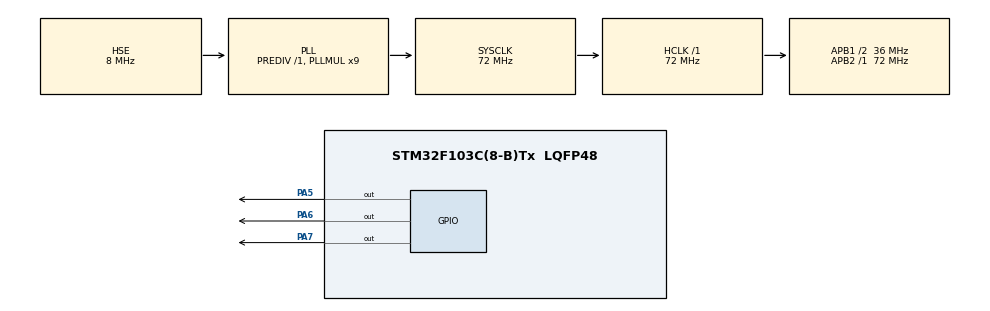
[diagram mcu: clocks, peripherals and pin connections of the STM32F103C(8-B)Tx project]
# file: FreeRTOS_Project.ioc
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Mcu.Family=STM32F1
Mcu.Name=STM32F103C(8-B)Tx
Mcu.Package=LQFP48
NVIC.PriorityGroup=NVIC_PRIORITYGROUP_4
NVIC.TIM2_IRQn=true\:15\:0\:false\:false\:true\:false\:true\:true
NVIC.TimeBase=TIM2_IRQn
NVIC.TimeBaseIP=TIM2
PA2.Signal=USART2_TX
PA3.Signal=USART2_RX
PA5.GPIO_PuPd=GPIO_PULLDOWN
PA5.Signal=GPIO_Output
PA6.GPIO_PuPd=GPIO_PULLDOWN
PA6.Signal=GPIO_Output
PA7.GPIO_PuPd=GPIO_PULLDOWN
PA7.Signal=GPIO_Output
PD0-OSC_IN.Mode=HSE-External-Oscillator
PD0-OSC_IN.Signal=RCC_OSC_IN
PD1-OSC_OUT.Mode=HSE-External-Oscillator
PD1-OSC_OUT.Signal=RCC_OSC_OUT
ProjectManager.HeapSize=0x200
ProjectManager.StackSize=0x400
ProjectManager.TargetToolchain=STM32CubeIDE
RCC.AHBFreq_Value=72000000
RCC.APB1CLKDivider=RCC_HCLK_DIV2
RCC.APB1Freq_Value=36000000
RCC.APB1TimFreq_Value=72000000
RCC.APB2Freq_Value=72000000
RCC.APB2TimFreq_Value=72000000
RCC.HCLKFreq_Value=72000000
RCC.PLLMUL=RCC_PLL_MUL9
RCC.PLLSourceVirtual=RCC_PLLSOURCE_HSE
RCC.SYSCLKFreq_VALUE=72000000
RCC.SYSCLKSource=RCC_SYSCLKSOURCE_PLLCLK
RCC.USBFreq_Value=72000000
VP_SYS_VS_ND.Mode=No_Debug
VP_SYS_VS_tim2.Mode=TIM2
board=custom

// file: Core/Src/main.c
/* USER CODE BEGIN Header */
/**
 ******************************************************************************
 * @file           : main.c
 * @brief          : Main program body
 ******************************************************************************
 * @attention
 *
 * Copyright (c) 2022 STMicroelectronics.
 * All rights reserved.
 *
 * This software is licensed under terms that can be found in the LICENSE file
 * in the root directory of this software component.
 * If no LICENSE file comes with this software, it is provided AS-IS.
 *
 ******************************************************************************
 */
/* USER CODE END Header */
#include "main.h"

/* USER CODE BEGIN Includes */
#include "FreeRTOS.h"
#include "task.h"
#include <stdio.h>
/* USER CODE END Includes */

/* USER CODE BEGIN PM */
#define    DWT_CONTROL     *((volatile uint32_t *)0xE0001000)
#define    SCB_DEMCR         *((volatile uint32_t *)0xE000EDFC)
/* USER CODE END PM */

void SystemClock_Config(void);
static void MX_GPIO_Init(void);
/* USER CODE BEGIN PFP */
static void task1_handler(void * parameters);
static void task2_handler(void * parameters);
extern void SEGGER_UART_init(long unsigned int);
/* USER CODE END PFP */

int main(void)
{
	/* USER CODE BEGIN 1 */
	TaskHandle_t task1_handle;
	TaskHandle_t task2_handle;
	BaseType_t status;
	/* USER CODE END 1 */

	/* MCU Configuration--------------------------------------------------------*/

	/* Reset of all peripherals, Initializes the Flash interface and the Systick. */
	HAL_Init();

	/* Configure the system clock */
	SystemClock_Config();

	/* USER CODE BEGIN SysInit */
	SEGGER_UART_init(230400);
	/* USER CODE END SysInit */

	/* Initialize all configured peripherals */
	MX_GPIO_Init();
	/* USER CODE BEGIN 2 */

	SCB_DEMCR  |= (1<<24);
	DWT_CONTROL|= (1<<0);

	SEGGER_SYSVIEW_Conf();

	status = xTaskCreate(task1_handler, "Task-1", 200, "Hello World from Task-1", 2, &task1_handle);
	configASSERT(status==pdPASS);
	status = xTaskCreate(task2_handler, "Task-2", 200, "Hello World from Task-2", 2, &task2_handle);
	configASSERT(status==pdPASS);
	vTaskStartScheduler();
	/* USER CODE END 2 */

	/* Infinite loop */
	while (1)
	{

	}
}

void SystemClock_Config(void)
{
	RCC_OscInitTypeDef RCC_OscInitStruct = {0};
	RCC_ClkInitTypeDef RCC_ClkInitStruct = {0};

	/** Initializes the RCC Oscillators according to the specified parameters
	 * in the RCC_OscInitTypeDef structure.
	 */
	RCC_OscInitStruct.OscillatorType = RCC_OSCILLATORTYPE_HSE;
	RCC_OscInitStruct.HSEState = RCC_HSE_ON;
	RCC_OscInitStruct.HSEPredivValue = RCC_HSE_PREDIV_DIV1;
	RCC_OscInitStruct.HSIState = RCC_HSI_ON;
	RCC_OscInitStruct.PLL.PLLState = RCC_PLL_ON;
	RCC_OscInitStruct.PLL.PLLSource = RCC_PLLSOURCE_HSE;
	RCC_OscInitStruct.PLL.PLLMUL = RCC_PLL_MUL9;
	if (HAL_RCC_OscConfig(&RCC_OscInitStruct) != HAL_OK)
	{
		Error_Handler();
	}

	/** Initializes the CPU, AHB and APB buses clocks
	 */
	RCC_ClkInitStruct.ClockType = RCC_CLOCKTYPE_HCLK|RCC_CLOCKTYPE_SYSCLK
			|RCC_CLOCKTYPE_PCLK1|RCC_CLOCKTYPE_PCLK2;
	RCC_ClkInitStruct.SYSCLKSource = RCC_SYSCLKSOURCE_PLLCLK;
	RCC_ClkInitStruct.AHBCLKDivider = RCC_SYSCLK_DIV1;
	RCC_ClkInitStruct.APB1CLKDivider = RCC_HCLK_DIV2;
	RCC_ClkInitStruct.APB2CLKDivider = RCC_HCLK_DIV1;

	if (HAL_RCC_ClockConfig(&RCC_ClkInitStruct, FLASH_LATENCY_2) != HAL_OK)
	{
		Error_Handler();
	}
}

static void MX_GPIO_Init(void)
{
	GPIO_InitTypeDef GPIO_InitStruct = {0};

	/* GPIO Ports Clock Enable */
	__HAL_RCC_GPIOD_CLK_ENABLE();
	__HAL_RCC_GPIOA_CLK_ENABLE();

	/*Configure GPIO pin Output Level */
	HAL_GPIO_WritePin(GPIOA, GPIO_PIN_5|GPIO_PIN_6|GPIO_PIN_7, GPIO_PIN_RESET);

	/*Configure GPIO pins : PA2 PA9 */
	GPIO_InitStruct.Pin = GPIO_PIN_2|GPIO_PIN_9;
	GPIO_InitStruct.Mode = GPIO_MODE_AF_PP;
	GPIO_InitStruct.Speed = GPIO_SPEED_FREQ_HIGH;
	HAL_GPIO_Init(GPIOA, &GPIO_InitStruct);

	/*Configure GPIO pins : PA3 PA10 */
	GPIO_InitStruct.Pin = GPIO_PIN_3|GPIO_PIN_10;
	GPIO_InitStruct.Mode = GPIO_MODE_INPUT;
	GPIO_InitStruct.Pull = GPIO_NOPULL;
	HAL_GPIO_Init(GPIOA, &GPIO_InitStruct);

	/*Configure GPIO pins : PA5 PA6 PA7 */
	GPIO_InitStruct.Pin = GPIO_PIN_5|GPIO_PIN_6|GPIO_PIN_7;
	GPIO_InitStruct.Mode = GPIO_MODE_OUTPUT_PP;
	GPIO_InitStruct.Pull = GPIO_PULLDOWN;
	GPIO_InitStruct.Speed = GPIO_SPEED_FREQ_LOW;
	HAL_GPIO_Init(GPIOA, &GPIO_InitStruct);

}

/* USER CODE BEGIN 4 */

static void task1_handler(void * parameters){

	while(1){
		SEGGER_SYSVIEW_PrintfTarget((char*)parameters);
		taskYIELD();
	}
}
static void task2_handler(void * parameters){

	while(1){
		SEGGER_SYSVIEW_PrintfTarget((char*)parameters);
		taskYIELD();
	}
}

/* USER CODE END 4 */

void HAL_TIM_PeriodElapsedCallback(TIM_HandleTypeDef *htim)
{
	if (htim->Instance == TIM2) {
		HAL_IncTick();
	}
}

void Error_Handler(void)
{
	__disable_irq();
	while (1)
	{
	}
}
